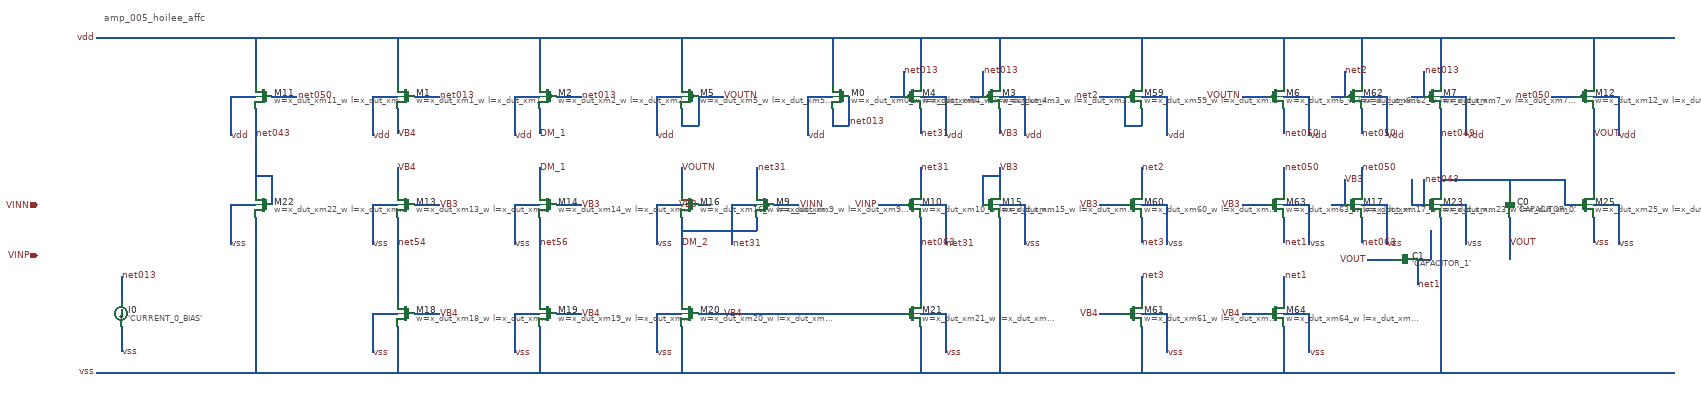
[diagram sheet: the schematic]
v {xschem version=3.4.6 file_version=1.2}
G {}
K {}
V {}
S {}
E {}
T {amp_005_hoilee_affc} -1910 -200 0 0 0.4 0.4 {}
C {devices/capa_np.sym} 1450 260 0 0 {name=C0 value='CAPACITOR_0'}
C {devices/capa_np.sym} 1200 390 1 0 {name=C1 value='CAPACITOR_1'}
C {devices/isource_np.sym} -1870 520 0 0 {name=I0 value='CURRENT_0_BIAS'}
C {devices/sg13_lv_pmos_np.sym} -150 0 0 1 {name=M0 model=sg13_lv_pmos spiceprefix=X w=x_dut_xm0_w l=x_dut_xm0_l m=x_dut_xm0_m}
C {devices/sg13_lv_pmos_np.sym} -1190 0 0 1 {name=M1 model=sg13_lv_pmos spiceprefix=X w=x_dut_xm1_w l=x_dut_xm1_l m=x_dut_xm1_m}
C {devices/sg13_lv_pmos_np.sym} 20 260 0 0 {name=M10 model=sg13_lv_pmos spiceprefix=X w=x_dut_xm10_w l=x_dut_xm10_l m=x_dut_xm10_m}
C {devices/sg13_lv_pmos_np.sym} -1530 0 0 1 {name=M11 model=sg13_lv_pmos spiceprefix=X w=x_dut_xm11_w l=x_dut_xm11_l m=x_dut_xm11_m}
C {devices/sg13_lv_pmos_np.sym} 1630 0 0 0 {name=M12 model=sg13_lv_pmos spiceprefix=X w=x_dut_xm12_w l=x_dut_xm12_l m=x_dut_xm12_m}
C {devices/sg13_lv_nmos_np.sym} -1190 260 0 1 {name=M13 model=sg13_lv_nmos spiceprefix=X w=x_dut_xm13_w l=x_dut_xm13_l m=x_dut_xm13_m}
C {devices/sg13_lv_nmos_np.sym} -850 260 0 1 {name=M14 model=sg13_lv_nmos spiceprefix=X w=x_dut_xm14_w l=x_dut_xm14_l m=x_dut_xm14_m}
C {devices/sg13_lv_nmos_np.sym} 210 260 0 0 {name=M15 model=sg13_lv_nmos spiceprefix=X w=x_dut_xm15_w l=x_dut_xm15_l m=x_dut_xm15_m}
C {devices/sg13_lv_nmos_np.sym} -510 260 0 1 {name=M16 model=sg13_lv_nmos spiceprefix=X w=x_dut_xm16_w l=x_dut_xm16_l m=x_dut_xm16_m}
C {devices/sg13_lv_nmos_np.sym} 1075 260 0 0 {name=M17 model=sg13_lv_nmos spiceprefix=X w=x_dut_xm17_w l=x_dut_xm17_l m=x_dut_xm17_m}
C {devices/sg13_lv_nmos_np.sym} -1190 520 0 1 {name=M18 model=sg13_lv_nmos spiceprefix=X w=x_dut_xm18_w l=x_dut_xm18_l m=x_dut_xm18_m}
C {devices/sg13_lv_nmos_np.sym} -850 520 0 1 {name=M19 model=sg13_lv_nmos spiceprefix=X w=x_dut_xm19_w l=x_dut_xm19_l m=x_dut_xm19_m}
C {devices/sg13_lv_pmos_np.sym} -850 0 0 1 {name=M2 model=sg13_lv_pmos spiceprefix=X w=x_dut_xm2_w l=x_dut_xm2_l m=x_dut_xm2_m}
C {devices/sg13_lv_nmos_np.sym} -510 520 0 1 {name=M20 model=sg13_lv_nmos spiceprefix=X w=x_dut_xm20_w l=x_dut_xm20_l m=x_dut_xm20_m}
C {devices/sg13_lv_nmos_np.sym} 20 520 0 0 {name=M21 model=sg13_lv_nmos spiceprefix=X w=x_dut_xm21_w l=x_dut_xm21_l m=x_dut_xm21_m}
C {devices/sg13_lv_nmos_np.sym} -1530 260 0 1 {name=M22 model=sg13_lv_nmos spiceprefix=X w=x_dut_xm22_w l=x_dut_xm22_l m=x_dut_xm22_m}
C {devices/sg13_lv_nmos_np.sym} 1265 260 0 0 {name=M23 model=sg13_lv_nmos spiceprefix=X w=x_dut_xm23_w l=x_dut_xm23_l m=x_dut_xm23_m}
C {devices/sg13_lv_nmos_np.sym} 1630 260 0 0 {name=M25 model=sg13_lv_nmos spiceprefix=X w=x_dut_xm25_w l=x_dut_xm25_l m=x_dut_xm25_m}
C {devices/sg13_lv_pmos_np.sym} 210 0 0 0 {name=M3 model=sg13_lv_pmos spiceprefix=X w=x_dut_xm3_w l=x_dut_xm3_l m=x_dut_xm3_m}
C {devices/sg13_lv_pmos_np.sym} 20 0 0 0 {name=M4 model=sg13_lv_pmos spiceprefix=X w=x_dut_xm4_w l=x_dut_xm4_l m=x_dut_xm4_m}
C {devices/sg13_lv_pmos_np.sym} -510 0 0 1 {name=M5 model=sg13_lv_pmos spiceprefix=X w=x_dut_xm5_w l=x_dut_xm5_l m=x_dut_xm5_m}
C {devices/sg13_lv_pmos_np.sym} 550 0 0 0 {name=M59 model=sg13_lv_pmos spiceprefix=X w=x_dut_xm59_w l=x_dut_xm59_l m=x_dut_xm59_m}
C {devices/sg13_lv_pmos_np.sym} 890 0 0 0 {name=M6 model=sg13_lv_pmos spiceprefix=X w=x_dut_xm6_w l=x_dut_xm6_l m=x_dut_xm6_m}
C {devices/sg13_lv_nmos_np.sym} 550 260 0 0 {name=M60 model=sg13_lv_nmos spiceprefix=X w=x_dut_xm60_w l=x_dut_xm60_l m=x_dut_xm60_m}
C {devices/sg13_lv_nmos_np.sym} 550 520 0 0 {name=M61 model=sg13_lv_nmos spiceprefix=X w=x_dut_xm61_w l=x_dut_xm61_l m=x_dut_xm61_m}
C {devices/sg13_lv_pmos_np.sym} 1075 0 0 0 {name=M62 model=sg13_lv_pmos spiceprefix=X w=x_dut_xm62_w l=x_dut_xm62_l m=x_dut_xm62_m}
C {devices/sg13_lv_nmos_np.sym} 890 260 0 0 {name=M63 model=sg13_lv_nmos spiceprefix=X w=x_dut_xm63_w l=x_dut_xm63_l m=x_dut_xm63_m}
C {devices/sg13_lv_nmos_np.sym} 890 520 0 0 {name=M64 model=sg13_lv_nmos spiceprefix=X w=x_dut_xm64_w l=x_dut_xm64_l m=x_dut_xm64_m}
C {devices/sg13_lv_pmos_np.sym} 1265 0 0 0 {name=M7 model=sg13_lv_pmos spiceprefix=X w=x_dut_xm7_w l=x_dut_xm7_l m=x_dut_xm7_m}
C {devices/sg13_lv_pmos_np.sym} -330 260 0 1 {name=M9 model=sg13_lv_pmos spiceprefix=X w=x_dut_xm9_w l=x_dut_xm9_l m=x_dut_xm9_m}
N -1870 430 -1870 490 {}
N -1870 550 -1870 610 {}
N -1610 0 -1610 94 {}
N -1610 260 -1610 354 {}
N -1550 -140 -1550 -30 {}
N -1550 30 -1550 230 {}
N -1550 290 -1550 660 {}
N -1510 190 -1510 260 {}
N -1270 0 -1270 94 {}
N -1270 260 -1270 354 {}
N -1270 520 -1270 614 {}
N -1210 -140 -1210 -30 {}
N -1210 30 -1210 90 {}
N -1210 170 -1210 230 {}
N -1210 290 -1210 490 {}
N -1210 550 -1210 660 {}
N -930 0 -930 94 {}
N -930 260 -930 354 {}
N -930 520 -930 614 {}
N -870 -140 -870 -30 {}
N -870 30 -870 90 {}
N -870 170 -870 230 {}
N -870 290 -870 490 {}
N -870 550 -870 660 {}
N -590 0 -590 94 {}
N -590 260 -590 354 {}
N -590 520 -590 614 {}
N -530 -140 -530 -30 {}
N -530 30 -530 70 {}
N -530 170 -530 230 {}
N -530 290 -530 490 {}
N -530 550 -530 660 {}
N -490 0 -490 70 {}
N -410 260 -410 354 {}
N -350 170 -350 230 {}
N -350 290 -350 320 {}
N -230 0 -230 94 {}
N -170 -140 -170 -30 {}
N -170 30 -170 70 {}
N -130 0 -130 70 {}
N 0 -60 0 0 {}
N 40 -140 40 -30 {}
N 40 30 40 90 {}
N 40 170 40 230 {}
N 40 290 40 490 {}
N 40 550 40 660 {}
N 100 0 100 94 {}
N 100 260 100 354 {}
N 100 520 100 614 {}
N 190 -60 190 0 {}
N 190 190 190 260 {}
N 230 -140 230 -30 {}
N 230 30 230 90 {}
N 230 170 230 230 {}
N 230 290 230 660 {}
N 290 0 290 94 {}
N 290 260 290 354 {}
N 530 0 530 70 {}
N 570 -140 570 -30 {}
N 570 30 570 70 {}
N 570 170 570 230 {}
N 570 290 570 350 {}
N 570 430 570 490 {}
N 570 550 570 660 {}
N 630 0 630 94 {}
N 630 260 630 354 {}
N 630 520 630 614 {}
N 910 -140 910 -30 {}
N 910 30 910 90 {}
N 910 170 910 230 {}
N 910 290 910 350 {}
N 910 430 910 490 {}
N 910 550 910 660 {}
N 970 0 970 94 {}
N 970 260 970 354 {}
N 970 520 970 614 {}
N 1055 -60 1055 0 {}
N 1055 200 1055 260 {}
N 1095 -140 1095 -30 {}
N 1095 30 1095 90 {}
N 1095 170 1095 230 {}
N 1095 290 1095 350 {}
N 1155 0 1155 94 {}
N 1155 260 1155 354 {}
N 1215 200 1215 260 {}
N 1230 390 1230 450 {}
N 1245 -60 1245 0 {}
N 1245 200 1245 260 {}
N 1260 320 1260 390 {}
N 1285 -140 1285 -30 {}
N 1285 30 1285 230 {}
N 1285 290 1285 660 {}
N 1345 0 1345 94 {}
N 1345 260 1345 354 {}
N 1450 200 1450 230 {}
N 1450 290 1450 390 {}
N 1580 200 1580 260 {}
N 1650 -140 1650 -30 {}
N 1650 30 1650 230 {}
N 1650 290 1650 350 {}
N 1710 0 1710 94 {}
N 1710 260 1710 354 {}
N -1930 -140 1845 -140 {}
N -1610 0 -1550 0 {}
N -1510 0 -1450 0 {}
N -1270 0 -1210 0 {}
N -1170 0 -1110 0 {}
N -930 0 -870 0 {}
N -830 0 -770 0 {}
N -590 0 -530 0 {}
N -490 0 -430 0 {}
N -230 0 -170 0 {}
N -30 0 0 0 {}
N 40 0 100 0 {}
N 160 0 190 0 {}
N 230 0 290 0 {}
N 470 0 530 0 {}
N 570 0 630 0 {}
N 810 0 870 0 {}
N 910 0 970 0 {}
N 1025 0 1055 0 {}
N 1095 0 1155 0 {}
N 1215 0 1245 0 {}
N 1285 0 1345 0 {}
N 1550 0 1610 0 {}
N 1650 0 1710 0 {}
N -530 70 -490 70 {}
N -170 70 -130 70 {}
N 530 70 570 70 {}
N -1550 190 -1510 190 {}
N 190 190 230 190 {}
N 1285 200 1580 200 {}
N -1610 260 -1550 260 {}
N -1270 260 -1210 260 {}
N -1170 260 -1110 260 {}
N -930 260 -870 260 {}
N -830 260 -770 260 {}
N -590 260 -530 260 {}
N -490 260 -460 260 {}
N -410 260 -350 260 {}
N -310 260 -250 260 {}
N -60 260 0 260 {}
N 40 260 100 260 {}
N 230 260 290 260 {}
N 470 260 530 260 {}
N 570 260 630 260 {}
N 810 260 870 260 {}
N 910 260 970 260 {}
N 1025 260 1055 260 {}
N 1095 260 1155 260 {}
N 1215 260 1245 260 {}
N 1285 260 1345 260 {}
N 1580 260 1610 260 {}
N 1650 260 1710 260 {}
N -530 320 -350 320 {}
N 1110 390 1170 390 {}
N 1230 390 1260 390 {}
N -1270 520 -1210 520 {}
N -1170 520 -1110 520 {}
N -930 520 -870 520 {}
N -830 520 -770 520 {}
N -590 520 -530 520 {}
N -490 520 0 520 {}
N 40 520 100 520 {}
N 470 520 530 520 {}
N 570 520 630 520 {}
N 810 520 870 520 {}
N 910 520 970 520 {}
N -1930 660 1845 660 {}
C {devices/lab_wire.sym} -1930 -140 0 0 {name=l0 lab=vdd}
C {devices/lab_wire.sym} -1930 660 0 0 {name=l1 lab=vss}
C {devices/lab_wire.sym} -870 90 2 0 {name=l2 lab=DM_1}
C {devices/lab_wire.sym} -870 170 0 1 {name=l3 lab=DM_1}
C {devices/lab_wire.sym} -530 350 2 0 {name=l4 lab=DM_2}
C {devices/lab_wire.sym} -1110 260 0 1 {name=l5 lab=VB3}
C {devices/lab_wire.sym} -770 260 0 1 {name=l6 lab=VB3}
C {devices/lab_wire.sym} -490 260 0 0 {name=l7 lab=VB3}
C {devices/lab_wire.sym} 230 170 0 1 {name=l8 lab=VB3}
C {devices/lab_wire.sym} 230 90 2 0 {name=l9 lab=VB3}
C {devices/lab_wire.sym} 470 260 0 0 {name=l10 lab=VB3}
C {devices/lab_wire.sym} 810 260 0 0 {name=l11 lab=VB3}
C {devices/lab_wire.sym} 1055 200 0 1 {name=l12 lab=VB3}
C {devices/lab_wire.sym} -1210 90 2 0 {name=l13 lab=VB4}
C {devices/lab_wire.sym} -1210 170 0 1 {name=l14 lab=VB4}
C {devices/lab_wire.sym} -1110 520 0 1 {name=l15 lab=VB4}
C {devices/lab_wire.sym} -770 520 0 1 {name=l16 lab=VB4}
C {devices/lab_wire.sym} -430 520 0 1 {name=l17 lab=VB4}
C {devices/lab_wire.sym} 470 520 0 0 {name=l18 lab=VB4}
C {devices/lab_wire.sym} 810 520 0 0 {name=l19 lab=VB4}
C {devices/lab_wire.sym} -250 260 0 1 {name=l20 lab=VINN}
C {devices/lab_wire.sym} -60 260 0 0 {name=l21 lab=VINP}
C {devices/lab_wire.sym} 1110 390 0 0 {name=l22 lab=VOUT}
C {devices/lab_wire.sym} 1450 350 2 0 {name=l23 lab=VOUT}
C {devices/lab_wire.sym} 1650 90 2 0 {name=l24 lab=VOUT}
C {devices/lab_wire.sym} -430 0 0 1 {name=l25 lab=VOUTN}
C {devices/lab_wire.sym} -530 170 0 1 {name=l26 lab=VOUTN}
C {devices/lab_wire.sym} 810 0 0 0 {name=l27 lab=VOUTN}
C {devices/lab_wire.sym} -1110 0 0 1 {name=l28 lab=net013}
C {devices/lab_wire.sym} -770 0 0 1 {name=l29 lab=net013}
C {devices/lab_wire.sym} -130 60 2 0 {name=l30 lab=net013}
C {devices/lab_wire.sym} 0 -60 0 1 {name=l31 lab=net013}
C {devices/lab_wire.sym} 190 -60 0 1 {name=l32 lab=net013}
C {devices/lab_wire.sym} 1245 -60 0 1 {name=l33 lab=net013}
C {devices/lab_wire.sym} -1550 90 2 0 {name=l34 lab=net043}
C {devices/lab_wire.sym} 1245 200 0 1 {name=l35 lab=net043}
C {devices/lab_wire.sym} 1285 90 2 0 {name=l36 lab=net049}
C {devices/lab_wire.sym} -1450 0 0 1 {name=l37 lab=net050}
C {devices/lab_wire.sym} 910 90 2 0 {name=l38 lab=net050}
C {devices/lab_wire.sym} 910 170 0 1 {name=l39 lab=net050}
C {devices/lab_wire.sym} 1095 90 2 0 {name=l40 lab=net050}
C {devices/lab_wire.sym} 1095 170 0 1 {name=l41 lab=net050}
C {devices/lab_wire.sym} 1550 0 0 0 {name=l42 lab=net050}
C {devices/lab_wire.sym} 40 350 2 0 {name=l43 lab=net063}
C {devices/lab_wire.sym} 1095 350 2 0 {name=l44 lab=net063}
C {devices/lab_wire.sym} 910 350 2 0 {name=l45 lab=net1}
C {devices/lab_wire.sym} 910 430 0 1 {name=l46 lab=net1}
C {devices/lab_wire.sym} 1230 450 2 0 {name=l47 lab=net1}
C {devices/lab_wire.sym} 470 0 0 0 {name=l48 lab=net2}
C {devices/lab_wire.sym} 570 170 0 1 {name=l49 lab=net2}
C {devices/lab_wire.sym} 1055 -60 0 1 {name=l50 lab=net2}
C {devices/lab_wire.sym} 570 350 2 0 {name=l51 lab=net3}
C {devices/lab_wire.sym} 570 430 0 1 {name=l52 lab=net3}
C {devices/lab_wire.sym} -350 170 0 1 {name=l53 lab=net31}
C {devices/lab_wire.sym} 40 90 2 0 {name=l54 lab=net31}
C {devices/lab_wire.sym} 40 170 0 1 {name=l55 lab=net31}
C {devices/lab_wire.sym} -1210 350 2 0 {name=l56 lab=net54}
C {devices/lab_wire.sym} -870 350 2 0 {name=l57 lab=net56}
C {devices/lab_wire.sym} 100 354 2 0 {name=l58 lab=net31}
C {devices/lab_wire.sym} -410 354 2 0 {name=l59 lab=net31}
C {devices/lab_wire.sym} -230 94 2 0 {name=l60 lab=vdd}
C {devices/lab_wire.sym} -1270 94 2 0 {name=l61 lab=vdd}
C {devices/lab_wire.sym} -1610 94 2 0 {name=l62 lab=vdd}
C {devices/lab_wire.sym} 1710 94 2 0 {name=l63 lab=vdd}
C {devices/lab_wire.sym} -930 94 2 0 {name=l64 lab=vdd}
C {devices/lab_wire.sym} 290 94 2 0 {name=l65 lab=vdd}
C {devices/lab_wire.sym} 100 94 2 0 {name=l66 lab=vdd}
C {devices/lab_wire.sym} -590 94 2 0 {name=l67 lab=vdd}
C {devices/lab_wire.sym} 630 94 2 0 {name=l68 lab=vdd}
C {devices/lab_wire.sym} 970 94 2 0 {name=l69 lab=vdd}
C {devices/lab_wire.sym} 1155 94 2 0 {name=l70 lab=vdd}
C {devices/lab_wire.sym} 1345 94 2 0 {name=l71 lab=vdd}
C {devices/lab_wire.sym} -1270 354 2 0 {name=l72 lab=vss}
C {devices/lab_wire.sym} -930 354 2 0 {name=l73 lab=vss}
C {devices/lab_wire.sym} 290 354 2 0 {name=l74 lab=vss}
C {devices/lab_wire.sym} -590 354 2 0 {name=l75 lab=vss}
C {devices/lab_wire.sym} 1155 354 2 0 {name=l76 lab=vss}
C {devices/lab_wire.sym} -1270 614 2 0 {name=l77 lab=vss}
C {devices/lab_wire.sym} -930 614 2 0 {name=l78 lab=vss}
C {devices/lab_wire.sym} -590 614 2 0 {name=l79 lab=vss}
C {devices/lab_wire.sym} 100 614 2 0 {name=l80 lab=vss}
C {devices/lab_wire.sym} -1610 354 2 0 {name=l81 lab=vss}
C {devices/lab_wire.sym} 1345 354 2 0 {name=l82 lab=vss}
C {devices/lab_wire.sym} 1710 354 2 0 {name=l83 lab=vss}
C {devices/lab_wire.sym} 630 354 2 0 {name=l84 lab=vss}
C {devices/lab_wire.sym} 630 614 2 0 {name=l85 lab=vss}
C {devices/lab_wire.sym} 970 354 2 0 {name=l86 lab=vss}
C {devices/lab_wire.sym} 970 614 2 0 {name=l87 lab=vss}
C {devices/lab_wire.sym} -1870 430 0 1 {name=l88 lab=net013}
C {devices/lab_wire.sym} -1870 610 2 0 {name=l89 lab=vss}
C {devices/lab_wire.sym} 1650 350 2 0 {name=l90 lab=vss}
C {devices/ipin.sym} -2070 260 0 0 {name=p0 lab=VINN}
C {devices/ipin.sym} -2070 380 0 0 {name=p1 lab=VINP}
